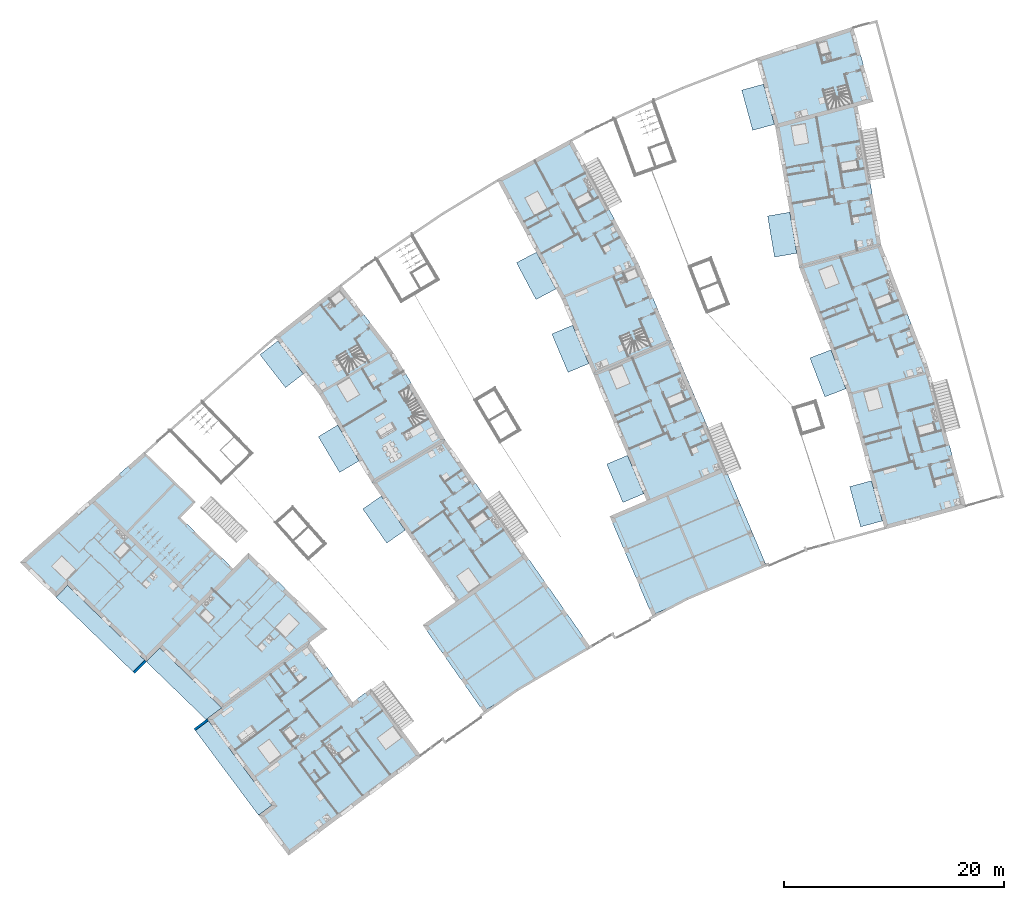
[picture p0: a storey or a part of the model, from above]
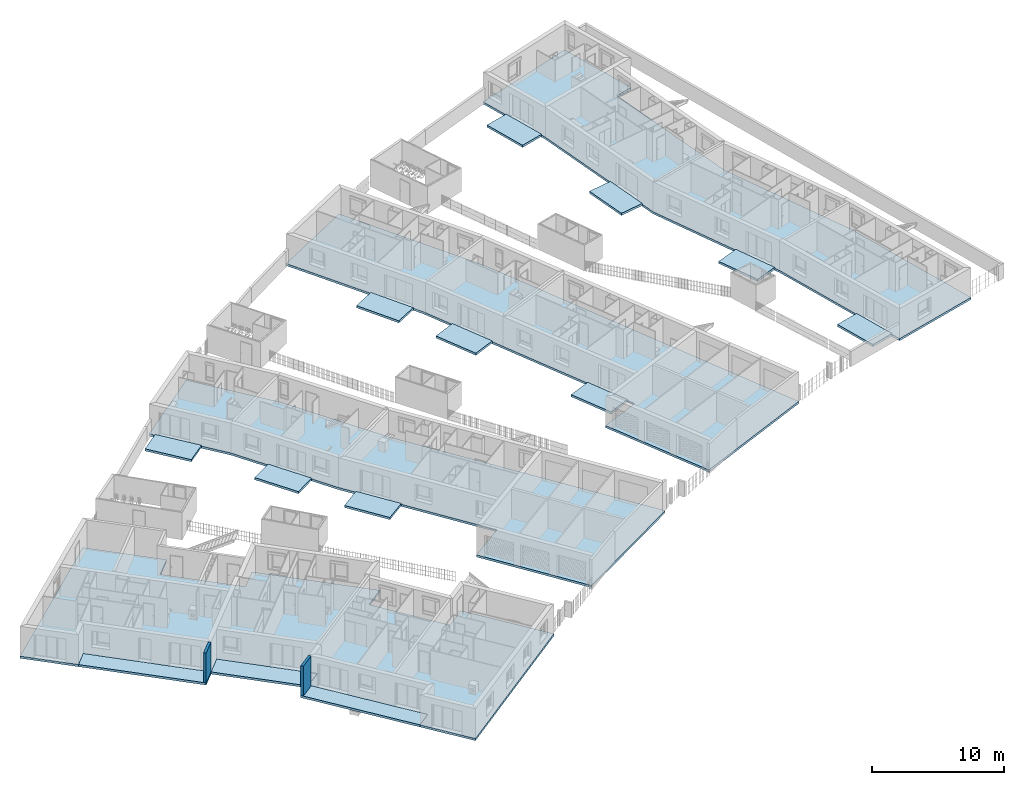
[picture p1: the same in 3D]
Properties of the parts of a building model (IFC2X3)

# File
Description: ViewDefinition [CoordinationView_V2.0], Option [Elements to export: Visible elements (on all stories)], Option [Partial Structure Display: Entire Model], Option [IFC Domain: All], Option [Structural Function: All Elements], Option [Convert Grid elements: On], Option [Convert IFC Annotations and Archicad 2D elements: Off], Option [Convert 2D symbols of Doors and Windows: Off], Option [Export geometries that Participates in Collision Detection only: Off], Option [Split complex elements: Off], Option [Material Preservation: Explode where necessary], Option [Elements in Solid Element Operations: Extruded/revolved], Option [Elements with junctions: Extruded/revolved without junctions], Option [IFC Model position: Survey Point and Project Origin], Option [Curtain Wall export mode: Container Element], Option [Railing export mode: Single Element], Option [Stair export mode: Container Element], Option [Properties To Export: All properties], Option [Space containment: Off], Option [Geometry to type objects: Off], Option [Element Properties: All], Option [Building Material Properties: Off], Option [Element Parameters: Off], Option [Component Parameters: Off], Option [IFC Base Quantities: Off], Option [Door Window Parameters: On], Option [IFC Space boundaries: Off], Option [Archicad Zone Categories as IFC Space classification data: Off], Option [Element Classifications: On]
File name: Z:\DOSSIERS EN COURS\CAN 24 - CLMH Authie Nord\CAN24 APD.ifc
Time: 2025-01-27T17:15:54
Author: Architect
Organization: Building Designer Office
Written by: DDS_IFC v3.0
Made in: IFC file generated by Graphisoft Archicad 27.0.0 FRA FULL Windows version (IFC add-on version: 3001 FRA FULL).
Authorization: The authorising person

# IfcSite, Site
RefLatitude: 48, 52, 0, 0; RefLongitude: 2, 20, 0, 0; RefElevation: 0 m

# IfcBuildingStorey (3)
In: Bâtiment
Name | Elevation (m)
rdc | 0
Etage 2 | 5.5
Etage 1 | 2.75

# IfcBuildingElementPart (102)
Name | In | Material
25 x Sans Trame 296962763 | rdc | Sans Trame 296962763
25 x Lame d'air 323202302 | rdc | Lame d'air 323202302
25 x Hachure solide 323202122 | rdc | Hachure solide 323202122
25 x Lame d'air 275581439 | rdc | Lame d'air 275581439
Isolant styromousse 301821074 | Etage 1 | Isolant styromousse 301821074
Parpaing 312445824 | Etage 1 | Parpaing 312445824

# IfcBuildingElementProxy (92)
AC_Pset_RenovationAndPhasing - Renovation Status: Existing
Name | In
29 x Obj.-019 | rdc
Obj.-376 | rdc
6 x Obj.-027 | rdc
Obj.-026 | rdc
35 x Obj.-003 | Etage 1
20 x Obj.-019 | Etage 1

# IfcBuildingElementProxy: Bicyclette 3D 27 (20)
In: rdc
Classification: Elément de construction non défini (Classification ARCHICAD)
AC_Pset_RenovationAndPhasing - Renovation Status: Existing

# IfcBuildingElementProxy: Cabine de douche 27 (4)
In: Etage 1
Classification: Meuble (Classification ARCHICAD)
Informations produit - Modèle: Non défini; N° de série: Non défini; Code-barres: Non défini; Date d'achat: JJ/MM/AAAA; Prix d'achat: 0
Fabrication - Fabricant: Non défini; Date de production: JJ/MM/AAA; Pays d'origine: Non défini; Site web: www.archicad.fr
Garantie - Interlocuteur: Non défini; Date début garantie: JJ/MM/AAAA; Date fin garantie: JJ/MM/AAAA; Exceptions: Non défini
Conditionnement - Matériau Conteneur: Non défini; Type d'Emballage: Non défini; Instructions Particulières: Non défini; Matière Emballage: Non défini
Environmental - Cycle de vie environmental: 0; Classe environnementale: 0; Durée de vie: 0; Energie stockée: Non défini; Entretien paysagé: 0
AC_Pset_RenovationAndPhasing - Renovation Status: Existing

# IfcBuildingElementProxy: Grille anti-effraction (17)
In: rdc
Classification: Elément de construction non défini (Classification ARCHICAD)
AC_Pset_RenovationAndPhasing - Renovation Status: Existing
Name
11 x Obj.-010
6 x Obj.-019

# IfcBuildingElementProxy: IfcBuildingElementProxy (178)
In: rdc
AC_Pset_RenovationAndPhasing - Renovation Status: Existing
Name | Material
18 x SS - 039 | Isolant styromousse 288701002
9 x MARCHE-537 | Lame d'air 275581351
9 x MARCHE-541 | Lame d'air 275581351
9 x MARCHE-539 | Lame d'air 275581351
9 x MARCHE-540 | Lame d'air 275581351
9 x MARCHE-542 | Lame d'air 275581351
9 x MARCHE-543 | Lame d'air 275581351
9 x MARCHE-538 | Lame d'air 275581351
9 x MARCHE-545 | Lame d'air 275581351
9 x MARCHE-547 | Lame d'air 275581351
9 x MARCHE-548 | Lame d'air 275581351
9 x MARCHE-546 | Lame d'air 275581351
9 x MARCHE-549 | Lame d'air 275581351
9 x MARCHE-550 | Lame d'air 275581351
9 x MARCHE-551 | Lame d'air 275581351
9 x MARCHE-552 | Lame d'air 275581351
9 x MARCHE-553 | Lame d'air 275581351
9 x MARCHE-544 | Lame d'air 275581351
7 x VOLEE-017 | Cloison 274992075

# IfcDiscreteAccessory: WC pour handicapés 27 (5)
Classification: Accessoire distinct (Classification ARCHICAD)
AC_Pset_RenovationAndPhasing - Renovation Status: Existing
Name | In
Obj.-003 | rdc
4 x Obj.-003 | Etage 1

# IfcDistributionElement: Chaudière à gaz 02 27 (13)
Classification: Elément de distribution (Classification ARCHICAD)
AC_Pset_RenovationAndPhasing - Renovation Status: Existing
Name | In
9 x Obj.-003 | rdc
4 x Obj.-003 | Etage 1

# IfcDistributionElement: Douche rectangulaire (23)
Classification: Elément de distribution (Classification ARCHICAD)
AC_Pset_RenovationAndPhasing - Renovation Status: Existing
Name | In
13 x Obj.-002 | rdc
10 x Obj.-002 | Etage 1

# IfcDistributionElement: Lavabo encastré rond (4)
In: Etage 1
Classification: Elément de distribution (Classification ARCHICAD)
AC_Pset_RenovationAndPhasing - Renovation Status: Existing

# IfcDistributionElement: Lavabo sur meuble 27 (40)
Classification: Elément de distribution (Classification ARCHICAD)
AC_Pset_RenovationAndPhasing - Renovation Status: Existing
Name | In
22 x Obj.-004 | rdc
18 x Obj.-004 | Etage 1

# IfcDoor (35)
Type - ParameterTakesPrecedence: no; Sizeable: no
OverallHeight: 2 m; Classification: Porte (Classification ARCHICAD)
AC_Pset_RenovationAndPhasing - Renovation Status: Existing
Name | In | OverallWidth (m)
Por-346 | rdc | 1.08037
8 x Por-301 | rdc | 2.4
2 x Por-302 | rdc | 2.4
2 x Por-303 | rdc | 2.4
Por-338 | rdc | 2.40877
Por-345 | rdc | 1.21647
Por-338 | rdc | 1.55452
Por-337 | rdc | 2.72114
Por-344 | rdc | 1.84344
Por-342 | rdc | 2.89654
Por-341 | rdc | 3.04698
Por-358 | rdc | 1.21647
Por-357 | rdc | 1.08037
Por-356 | rdc | 1.21647
Por-354 | rdc | 1.08037
Por-353 | rdc | 1.20034
Por-352 | rdc | 1.08037
Por-351 | rdc | 1.21647
Por-350 | rdc | 1.08037
Por-349 | rdc | 1.21647
Por-348 | rdc | 1.08037
Por-343 | rdc | 1.81551
Por-350 | Etage 1 | 1.08037
Por-351 | Etage 1 | 1.21647
Por-358 | Etage 1 | 1.21647
Por-357 | Etage 1 | 1.08037

# IfcDoor: Porte_1v (214)
Type - ParameterTakesPrecedence: no; Sizeable: no
OverallHeight: 2.04 m; Classification: Porte (Classification ARCHICAD)
AC_Pset_RenovationAndPhasing - Renovation Status: Existing
Name | In | OverallWidth (m)
Por-311 | rdc | 0.83
10 x Por-301 | rdc | 0.83
14 x Por-300 | rdc | 0.93
3 x Por-303 | rdc | 0.93
Por-299 | rdc | 0.93
37 x Por-299 | rdc | 0.83
7 x Por-320 | rdc | 0.467405
8 x Por-290 | rdc | 0.93
2 x Por-309 | rdc | 0.83
7 x Por-303 | rdc | 0.83
7 x Por-302 | rdc | 0.83
Por-302 | rdc | 0.93
Por-301 | rdc | 0.93
Por-286 | rdc | 0.83
Por-288 | rdc | 0.83
6 x Por-308 | rdc | 0.83
Por-317 | rdc | 0.83
Por-314 | rdc | 0.83
Por-316 | rdc | 0.83
Por-315 | rdc | 0.83
4 x Por-310 | rdc | 0.83
Por-313 | rdc | 0.83
Por-297 | rdc | 0.93
Por-300 | rdc | 1.03
6 x Por-301 | Etage 1 | 0.83
23 x Por-299 | Etage 1 | 0.83
4 x Por-309 | Etage 1 | 0.83
2 x Por-311 | Etage 1 | 0.83
6 x Por-310 | Etage 1 | 0.83
12 x Por-308 | Etage 1 | 0.83
Por-315 | Etage 1 | 0.83
7 x Por-304 | Etage 1 | 0.83
7 x Por-303 | Etage 1 | 0.83
7 x Por-302 | Etage 1 | 0.83
3 x Por-320 | Etage 1 | 0.467405
3 x Por-297 | Etage 1 | 0.93
Por-314 | Etage 1 | 0.83
Por-316 | Etage 1 | 0.83
2 x Por-293 | Etage 1 | 0.93
2 x Por-299 | Etage 1 | 0.93
2 x Por-303 | Etage 1 | 0.93
Por-294 | Etage 1 | 0.93
Por-300 | Etage 1 | 0.83
Por-291 | Etage 1 | 0.83
Por-290 | Etage 1 | 0.83
Por-289 | Etage 1 | 0.83
Por-313 | Etage 1 | 0.83
Por-317 | Etage 1 | 0.83

# IfcFurnishingElement: Canapé 5 (4)
Classification: Mobilier (Classification ARCHICAD)
AC_Pset_RenovationAndPhasing - Renovation Status: Existing
Name | In
2 x Obj.-375 | rdc
2 x Obj.-375 | Etage 1

# IfcFurnishingElement: Lit double 01 (20)
Classification: Mobilier (Classification ARCHICAD)
AC_Pset_RenovationAndPhasing - Renovation Status: Existing
Name | In
11 x Obj.-002 | rdc
9 x Obj.-002 | Etage 1

# IfcFurnishingElement: Machine à laver (25)
Classification: Mobilier (Classification ARCHICAD)
AC_Pset_RenovationAndPhasing - Renovation Status: Existing
Name | In
15 x Obj.-019 | rdc
10 x Obj.-019 | Etage 1

# IfcFurnishingElement: Meuble à plans 27 (21)
Classification: Mobilier (Classification ARCHICAD)
AC_Pset_RenovationAndPhasing - Renovation Status: Existing
Name | In
11 x Obj.-376 | rdc
10 x Obj.-376 | Etage 1

# IfcMember: IfcMember (203)
In: rdc
Classification: Membre (Classification ARCHICAD); Material: Lame d'air 275581351
AC_Pset_RenovationAndPhasing - Renovation Status: Existing
Name
7 x C-MARCHE-231
7 x C-MARCHE-232
7 x C-MARCHE-233
7 x C-MARCHE-234
7 x C-MARCHE-235
7 x C-MARCHE-236
7 x C-MARCHE-237
7 x C-MARCHE-238
7 x C-MARCHE-244
7 x C-MARCHE-243
7 x C-MARCHE-242
7 x C-MARCHE-241
7 x C-MARCHE-239
7 x C-MARCHE-240
7 x MARCHE-224
7 x C-MARCHE-245
7 x MARCHE-225
7 x MARCHE-226
7 x MARCHE-227
7 x MARCHE-230
7 x MARCHE-223
7 x MARCHE-229
7 x MARCHE-232
7 x MARCHE-233
7 x MARCHE-234
7 x MARCHE-235
7 x MARCHE-231
7 x MARCHE-236
7 x MARCHE-228

# IfcSlab: 100 % 3085578557 200 (11)
In: Etage 1
Type - PredefinedType: FLOOR
Classification: Dalle (Classification ARCHICAD); Material: 100 % 3085578557 0.2 m
AC_Pset_RenovationAndPhasing - Renovation Status: Existing

# IfcSlab: ANSI31 297159430 200 (26)
Type - PredefinedType: FLOOR
Classification: Dalle (Classification ARCHICAD); Material: ANSI31 297159430 0.2 m
AC_Pset_RenovationAndPhasing - Renovation Status: Existing
Name | In
13 x Dalle-099 | rdc
2 x Dalle-098 | Etage 1
4 x Dalle-096 | Etage 1
Dalle-097 | Etage 1
6 x Dalle-104 | Etage 2

# IfcSlab: AS_EMPTY 272048125 200 (12)
Type - PredefinedType: FLOOR
Classification: Dalle (Classification ARCHICAD); Material: AS_EMPTY 272048125 0.2 m
AC_Pset_RenovationAndPhasing - Renovation Status: Existing
Name | In
Dalle-100 | rdc
Dalle-098 | rdc
Dalle-097 | rdc
Dalle-099 | rdc
Dalle-096 | Etage 1
Dalle-094 | Etage 1
2 x Dalle-093 | Etage 1
Dalle-088 | Etage 1
Dalle-089 | Etage 1
Dalle-090 | Etage 1
Dalle-095 | Etage 1

# IfcSlab: MANQUANT 217, Toit-041
In: Etage 2
Type - PredefinedType: ROOF
Classification: Toit (Classification ARCHICAD); Material: MANQUANT 0.217216 m
AC_Pset_RenovationAndPhasing - Renovation Status: Existing
Pset_SlabCommon - IsExternal: yes; LoadBearing: no

# IfcSlab: MANQUANT 227, Toit-041
In: Etage 2
Type - PredefinedType: ROOF
Classification: Toit (Classification ARCHICAD); Material: MANQUANT 0.226976 m
AC_Pset_RenovationAndPhasing - Renovation Status: Existing
Pset_SlabCommon - IsExternal: yes; LoadBearing: no

# IfcSlab: MANQUANT 229, Toit-041
In: Etage 2
Type - PredefinedType: ROOF
Classification: Toit (Classification ARCHICAD); Material: MANQUANT 0.229386 m
AC_Pset_RenovationAndPhasing - Renovation Status: Existing
Pset_SlabCommon - IsExternal: yes; LoadBearing: no

# IfcSlab: MANQUANT 235 (12)
Type - PredefinedType: ROOF
Classification: Toit (Classification ARCHICAD); Material: MANQUANT 0.234923 m
AC_Pset_RenovationAndPhasing - Renovation Status: Existing
Pset_SlabCommon - IsExternal: yes; LoadBearing: no
Name | In
7 x Toit-041 | Etage 1
5 x Toit-041 | Etage 2

# IfcSlab: MANQUANT 237, Toit-041
In: Etage 2
Type - PredefinedType: ROOF
Classification: Toit (Classification ARCHICAD); Material: MANQUANT 0.236613 m
Pset_SlabCommon - IsExternal: yes; LoadBearing: no
AC_Pset_RenovationAndPhasing - Renovation Status: Existing

# IfcSlab: MANQUANT 243, Toit-041
In: Etage 2
Type - PredefinedType: ROOF
Classification: Toit (Classification ARCHICAD); Material: MANQUANT 0.242638 m
AC_Pset_RenovationAndPhasing - Renovation Status: Existing
Pset_SlabCommon - IsExternal: yes; LoadBearing: no

# IfcSlab: MANQUANT 245, Toit-041
In: Etage 2
Type - PredefinedType: ROOF
Classification: Toit (Classification ARCHICAD); Material: MANQUANT 0.245183 m
AC_Pset_RenovationAndPhasing - Renovation Status: Existing
Pset_SlabCommon - IsExternal: yes; LoadBearing: no

# IfcSlab: MANQUANT 246, Toit-041
In: Etage 2
Type - PredefinedType: ROOF
Classification: Toit (Classification ARCHICAD); Material: MANQUANT 0.245784 m
AC_Pset_RenovationAndPhasing - Renovation Status: Existing
Pset_SlabCommon - IsExternal: yes; LoadBearing: no

# IfcStair (16)
In: rdc
Classification: Escalier (Classification ARCHICAD)
AC_Pset_RenovationAndPhasing - Renovation Status: Existing
Name
9 x ESC-028
7 x ESC-014

# IfcWall: 1/Ossatur bois 160 non isol 160 (25)
In: rdc
Classification: Mur (Classification ARCHICAD)
AC_Pset_RenovationAndPhasing - Renovation Status: Existing
Name
7 x Mur-110
10 x Mur-108
5 x Mur-111
3 x Mur-109

# IfcWall: Beton 22 0836643198 220 (3)
In: rdc
Classification: Mur (Classification ARCHICAD); Material: Parpaing 312445824
AC_Pset_RenovationAndPhasing - Renovation Status: Existing

# IfcWall: Cloison 70 0826278243 70 (9)
In: rdc
Classification: Mur (Classification ARCHICAD); Material: Hachure solide 268963992
AC_Pset_RenovationAndPhasing - Renovation Status: Existing
Name
Mur-152
Mur-150
4 x Mur-149
Mur-151
Mur-153
Mur-154

# IfcWall: acrotère 22 220 (12)
In: Etage 2
Classification: Mur (Classification ARCHICAD); Material: Empty Fill 3000033799
AC_Pset_RenovationAndPhasing - Renovation Status: Existing
Name
9 x Mur-136
2 x Mur-135
Mur-133

# IfcWall: isol int 22+16 0836643197 380, Mur-113
In: Etage 1
Classification: Mur (Classification ARCHICAD)
AC_Pset_RenovationAndPhasing - Renovation Status: Existing

# IfcWallStandardCase: Beton 10 100 (4)
In: rdc
Classification: Mur (Classification ARCHICAD); Material: Parpaing 314940890 0.1 m
AC_Pset_RenovationAndPhasing - Renovation Status: Existing

# IfcWallStandardCase: Beton 18 180, Mur-113
In: Etage 1
Classification: Mur (Classification ARCHICAD); Material: Parpaing 314940890 0.18 m
AC_Pset_RenovationAndPhasing - Renovation Status: Existing

# IfcWallStandardCase: Beton 20 200 (6)
Classification: Mur (Classification ARCHICAD); Material: Parpaing 314940890 0.2 m
AC_Pset_RenovationAndPhasing - Renovation Status: Existing
Name | In
4 x Mur-105 | rdc
2 x Mur-105 | Etage 1

# IfcWallStandardCase: Beton 22 0836643197 220 (17)
Classification: Mur (Classification ARCHICAD); Material: Parpaing 314940890 0.22 m
AC_Pset_RenovationAndPhasing - Renovation Status: Existing
Name | In
8 x Mur-113 | rdc
6 x Mur-105 | rdc
2 x Mur-113 | Etage 1
Mur-105 | Etage 1

# IfcWallStandardCase: Beton 22 0836643198 220 (13)
Classification: Mur (Classification ARCHICAD); Material: Parpaing 312445824 0.22 m
AC_Pset_RenovationAndPhasing - Renovation Status: Existing
Name | In
4 x Mur-105 | rdc
5 x Mur-108 | rdc
Mur-106 | rdc
2 x Mur-107 | rdc
Mur-105 | Etage 1

# IfcWallStandardCase: Cloison 70 0826278243 70 (426)
Classification: Mur (Classification ARCHICAD); Material: Hachure solide 268963992 0.07 m
AC_Pset_RenovationAndPhasing - Renovation Status: Existing
Name | In
217 x Mur-149 | rdc
178 x Mur-149 | Etage 1
31 x Mur-150 | Etage 1

# IfcWallStandardCase: MANQUANT 200 (6)
In: rdc
Classification: Mur (Classification ARCHICAD); Material: MANQUANT 0.2 m
AC_Pset_RenovationAndPhasing - Renovation Status: Existing

# IfcWallStandardCase: acrotère 20 200, Mur-112
In: Etage 1
Classification: Mur (Classification ARCHICAD); Material: Empty Fill 292498448 0.2 m
AC_Pset_RenovationAndPhasing - Renovation Status: Existing

# IfcWallStandardCase: acrotère 22 220 (61)
Classification: Mur (Classification ARCHICAD); Material: Empty Fill 3000033799 0.22 m
AC_Pset_RenovationAndPhasing - Renovation Status: Existing
Name | In
11 x Mur-108 | rdc
Mur-109 | rdc
6 x Mur-105 | Etage 1
2 x Mur-108 | Etage 1
2 x Mur-107 | Etage 1
Mur-106 | Etage 1
2 x Mur-112 | Etage 1
Mur-111 | Etage 1
Mur-110 | Etage 1
31 x Mur-136 | Etage 2
3 x Mur-135 | Etage 2

# IfcWallStandardCase: isol int 22+16 0836643197 380 (101)
Classification: Mur (Classification ARCHICAD); Material: Parpaing 312445824 0.22 m, Isolant styromousse 301821074 0.16 m
AC_Pset_RenovationAndPhasing - Renovation Status: Existing
Name | In
5 x Mur-115 | rdc
2 x Mur-114 | rdc
33 x Mur-113 | rdc
4 x Mur-112 | rdc
5 x Mur-116 | rdc
5 x Mur-115 | Etage 1
38 x Mur-113 | Etage 1
6 x Mur-114 | Etage 1
3 x Mur-116 | Etage 1

# IfcWindow: Fenêtre variable 27 (2)
In: rdc
Type - OperationType: DOUBLE_PANEL_HORIZONTAL; ParameterTakesPrecedence: no; Sizeable: no
Type - Window Lining Properties - LiningDepth: 0.05 m; LiningThickness: 0.05 m; TransomThickness: 0.05 m; FirstTransomOffset: 0.2
Type - Window Panel Properties - Panel 1 - OperationType: TILTANDTURNLEFTHAND; PanelPosition: TOP; FrameDepth: 0.05 m; FrameThickness: 0.05 m
Type - Window Panel Properties - Panel 2 - OperationType: FIXEDCASEMENT; PanelPosition: BOTTOM
OverallHeight: 1.5 m; OverallWidth: 0.7 m; Classification: Fenêtre (Classification ARCHICAD)
AC_Pset_RenovationAndPhasing - Renovation Status: Existing
Name
Fen-050
Fen-047

# IfcWindow: Fenêtre variable 27 (2)
In: rdc
Type - OperationType: DOUBLE_PANEL_HORIZONTAL; ParameterTakesPrecedence: no; Sizeable: no
Type - Window Lining Properties - LiningDepth: 0.05 m; LiningThickness: 0.05 m; TransomThickness: 0.05 m; FirstTransomOffset: 0.2
Type - Window Panel Properties - Panel 1 - OperationType: TILTANDTURNRIGHTHAND; PanelPosition: TOP; FrameDepth: 0.05 m; FrameThickness: 0.05 m
Type - Window Panel Properties - Panel 2 - OperationType: FIXEDCASEMENT; PanelPosition: BOTTOM
OverallHeight: 1.5 m; OverallWidth: 0.7 m; Classification: Fenêtre (Classification ARCHICAD)
AC_Pset_RenovationAndPhasing - Renovation Status: Existing

# IfcWindow: Fenêtre variable 27 (2)
In: Etage 1
Type - OperationType: DOUBLE_PANEL_HORIZONTAL; ParameterTakesPrecedence: no; Sizeable: no
Type - Window Lining Properties - LiningDepth: 0.05 m; LiningThickness: 0.05 m; TransomThickness: 0.05 m; FirstTransomOffset: 0.458716
Type - Window Panel Properties - Panel 1 - OperationType: TILTANDTURNRIGHTHAND; PanelPosition: TOP; FrameDepth: 0.05 m; FrameThickness: 0.05 m
Type - Window Panel Properties - Panel 2 - OperationType: FIXEDCASEMENT; PanelPosition: BOTTOM
OverallHeight: 2.18 m; OverallWidth: 1 m; Classification: Fenêtre (Classification ARCHICAD)
AC_Pset_RenovationAndPhasing - Renovation Status: Existing

# IfcWindow: Fenêtre variable 27 (4)
In: rdc
Type - OperationType: DOUBLE_PANEL_VERTICAL; ParameterTakesPrecedence: no; Sizeable: no
Type - Window Lining Properties - LiningDepth: 0.05 m; LiningThickness: 0.05 m; MullionThickness: 0.05 m; FirstMullionOffset: 0.255793
Type - Window Panel Properties - Panel 1 - OperationType: SIDEHUNGLEFTHAND; PanelPosition: RIGHT; FrameDepth: 0.05 m; FrameThickness: 0.05 m
Type - Window Panel Properties - Panel 2 - OperationType: FIXEDCASEMENT; PanelPosition: LEFT
OverallHeight: 1.2 m; OverallWidth: 1.4 m; Classification: Fenêtre (Classification ARCHICAD)
AC_Pset_RenovationAndPhasing - Renovation Status: Existing

# IfcWindow: Fenêtre variable 27, Fen-045
In: rdc
Type - OperationType: DOUBLE_PANEL_VERTICAL; ParameterTakesPrecedence: no; Sizeable: no
Type - Window Lining Properties - LiningDepth: 0.05 m; LiningThickness: 0.05 m; MullionThickness: 0.05 m; FirstMullionOffset: 0.744207
Type - Window Panel Properties - Panel 1 - OperationType: SIDEHUNGRIGHTHAND; PanelPosition: LEFT; FrameDepth: 0.05 m; FrameThickness: 0.05 m
Type - Window Panel Properties - Panel 2 - OperationType: FIXEDCASEMENT; PanelPosition: RIGHT
OverallHeight: 1.2 m; OverallWidth: 1.4 m; Classification: Fenêtre (Classification ARCHICAD)
AC_Pset_RenovationAndPhasing - Renovation Status: Existing

# IfcWindow: Fenêtre variable 27 (5)
In: Etage 1
Type - OperationType: SINGLE_PANEL; ParameterTakesPrecedence: no; Sizeable: no
Type - Window Lining Properties - LiningDepth: 0.05 m; LiningThickness: 0.05 m
Type - Window Panel Properties - Panel 1 - OperationType: TILTANDTURNLEFTHAND; PanelPosition: MIDDLE; FrameDepth: 0.05 m; FrameThickness: 0.05 m
OverallHeight: 2.18 m; OverallWidth: 1 m; Classification: Fenêtre (Classification ARCHICAD)
AC_Pset_RenovationAndPhasing - Renovation Status: Existing

# IfcWindow: Fenêtre variable 27, Fen-052
In: rdc
Type - OperationType: SINGLE_PANEL; ParameterTakesPrecedence: no; Sizeable: no
Type - Window Lining Properties - LiningDepth: 0.05 m; LiningThickness: 0.05 m
Type - Window Panel Properties - Panel 1 - OperationType: TILTANDTURNRIGHTHAND; PanelPosition: MIDDLE; FrameDepth: 0.05 m; FrameThickness: 0.05 m
OverallHeight: 2.18 m; OverallWidth: 1 m; Classification: Fenêtre (Classification ARCHICAD)
AC_Pset_RenovationAndPhasing - Renovation Status: Existing

# IfcWindow: Fenêtre variable 27 (42)
Type - OperationType: TRIPLE_PANEL_LEFT; ParameterTakesPrecedence: no; Sizeable: no
Type - Window Lining Properties - LiningDepth: 0.05 m; LiningThickness: 0.05 m; TransomThickness: 0.05 m; MullionThickness: 0.05 m; FirstTransomOffset: 0.2; FirstMullionOffset: 0.255793
Type - Window Panel Properties - Panel 1 - OperationType: SIDEHUNGLEFTHAND; PanelPosition: TOP; FrameDepth: 0.05 m; FrameThickness: 0.05 m
Type - Window Panel Properties - Panel 2 - OperationType: FIXEDCASEMENT; PanelPosition: BOTTOM
Type - Window Panel Properties - Panel 3 - OperationType: FIXEDCASEMENT; PanelPosition: LEFT
OverallHeight: 1.5 m; OverallWidth: 1.4 m; Classification: Fenêtre (Classification ARCHICAD)
AC_Pset_RenovationAndPhasing - Renovation Status: Existing
Name | In
19 x Fen-045 | rdc
23 x Fen-045 | Etage 1

# IfcWindow: Fenêtre variable 27, Fen-045
In: Etage 1
Type - OperationType: TRIPLE_PANEL_LEFT; ParameterTakesPrecedence: no; Sizeable: no
Type - Window Lining Properties - LiningDepth: 0.05 m; LiningThickness: 0.05 m; TransomThickness: 0.05 m; MullionThickness: 0.05 m; FirstTransomOffset: 0.454545; FirstMullionOffset: 0.255793
Type - Window Panel Properties - Panel 1 - OperationType: SIDEHUNGLEFTHAND; PanelPosition: TOP; FrameDepth: 0.05 m; FrameThickness: 0.05 m
Type - Window Panel Properties - Panel 2 - OperationType: FIXEDCASEMENT; PanelPosition: BOTTOM
Type - Window Panel Properties - Panel 3 - OperationType: FIXEDCASEMENT; PanelPosition: LEFT
OverallHeight: 2.2 m; OverallWidth: 1.4 m; Classification: Fenêtre (Classification ARCHICAD)
AC_Pset_RenovationAndPhasing - Renovation Status: Existing

# IfcWindow: Fenêtre variable 27 (40)
Type - OperationType: TRIPLE_PANEL_RIGHT; ParameterTakesPrecedence: no; Sizeable: no
Type - Window Lining Properties - LiningDepth: 0.05 m; LiningThickness: 0.05 m; TransomThickness: 0.05 m; MullionThickness: 0.05 m; FirstTransomOffset: 0.2; FirstMullionOffset: 0.744207
Type - Window Panel Properties - Panel 1 - OperationType: SIDEHUNGRIGHTHAND; PanelPosition: TOP; FrameDepth: 0.05 m; FrameThickness: 0.05 m
Type - Window Panel Properties - Panel 2 - OperationType: FIXEDCASEMENT; PanelPosition: BOTTOM
Type - Window Panel Properties - Panel 3 - OperationType: FIXEDCASEMENT; PanelPosition: RIGHT
OverallHeight: 1.5 m; OverallWidth: 1.4 m; Classification: Fenêtre (Classification ARCHICAD)
AC_Pset_RenovationAndPhasing - Renovation Status: Existing
Name | In
19 x Fen-045 | rdc
21 x Fen-045 | Etage 1

# IfcWindow: Fenêtre variable 27 (18)
Type - OperationType: TRIPLE_PANEL_VERTICAL; ParameterTakesPrecedence: no; Sizeable: no
Type - Window Lining Properties - LiningDepth: 0.05 m; LiningThickness: 0.05 m; MullionThickness: 0.05 m; FirstMullionOffset: 0.302; SecondMullionOffset: 0.648
Type - Window Panel Properties - Panel 1 - OperationType: SIDEHUNGLEFTHAND; PanelPosition: MIDDLE; FrameDepth: 0.05 m; FrameThickness: 0.05 m
Type - Window Panel Properties - Panel 2 - OperationType: SIDEHUNGRIGHTHAND; PanelPosition: RIGHT; FrameDepth: 0.05 m; FrameThickness: 0.05 m
Type - Window Panel Properties - Panel 3 - OperationType: FIXEDCASEMENT; PanelPosition: LEFT
OverallHeight: 2.18 m; OverallWidth: 2.5 m; Classification: Fenêtre (Classification ARCHICAD)
AC_Pset_RenovationAndPhasing - Renovation Status: Existing
Name | In
9 x Fen-045 | rdc
Fen-050 | rdc
Fen-053 | rdc
Fen-050 | Etage 1
5 x Fen-045 | Etage 1
Fen-053 | Etage 1

# IfcWindow: Fenêtre variable 27 (13)
Type - OperationType: TRIPLE_PANEL_VERTICAL; ParameterTakesPrecedence: no; Sizeable: no
Type - Window Lining Properties - LiningDepth: 0.05 m; LiningThickness: 0.05 m; MullionThickness: 0.05 m; FirstMullionOffset: 0.352; SecondMullionOffset: 0.698
Type - Window Panel Properties - Panel 1 - OperationType: SIDEHUNGRIGHTHAND; PanelPosition: MIDDLE; FrameDepth: 0.05 m; FrameThickness: 0.05 m
Type - Window Panel Properties - Panel 2 - OperationType: SIDEHUNGLEFTHAND; PanelPosition: LEFT; FrameDepth: 0.05 m; FrameThickness: 0.05 m
Type - Window Panel Properties - Panel 3 - OperationType: FIXEDCASEMENT; PanelPosition: RIGHT
OverallWidth: 2.5 m; Classification: Fenêtre (Classification ARCHICAD)
AC_Pset_RenovationAndPhasing - Renovation Status: Existing
Name | In | OverallHeight (m)
Fen-050 | rdc | 2.18
4 x Fen-045 | rdc | 2.18
Fen-045 | Etage 1 | 2.09978
6 x Fen-045 | Etage 1 | 2.18
Fen-050 | Etage 1 | 2.18
